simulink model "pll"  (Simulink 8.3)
settings: Solver=ode45  StartTime=0.0  StopTime=3e-08  RelTol=1e-3

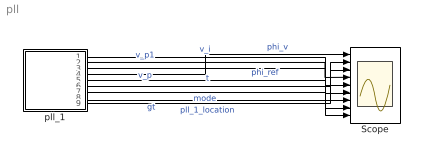
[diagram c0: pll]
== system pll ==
  Scope : Scope  NumInputPorts=9
  pll_1 : Stateflow chart  TreatAsAtomicUnit=on
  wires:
  pll_1/4(phi_v_out) -> Scope/1  "phi_v"
  pll_1/6(t_out) -> Scope/2  "t"
  pll_1/9(pll_1_location) -> Scope/3  "pll_1_location"
  pll_1/2(v_p1_out) -> Scope/4  "v_p1"
  pll_1/5(phi_ref_out) -> Scope/5  "phi_ref"
  pll_1/3(v_p_out) -> Scope/6  "v_p"
  pll_1/8(gt_out) -> Scope/7  "gt"
  pll_1/1(v_i_out) -> Scope/8  "v_i"
  pll_1/7(mode_out) -> Scope/9  "mode"

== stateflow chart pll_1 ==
  state up_1
    du:
    v_i_dot = Ii_up / C_i;
    v_p1_dot = -1 * v_p1 / C_p1 * (1 / R_p2 + 1 / R_p3) + v_p / (C_p1 * R_p3) + Ip_up / C_p1;
    v_p_dot = v_p1 / (C_p3 * R_p3) - v_p / (C_p3 * R_p3);
    phi_v_dot = v_i * K_i / N + v_p * K_p / N + 6.28 * f_0 / N;
    phi_ref_dot = 6.28 * f_ref;
    mode_dot = 0;
    gt_dot = 1;
    v_i_out=v_i;
    v_p1_out=v_p1;
    v_p_out=v_p;
    phi_v_out=phi_v;
    phi_ref_out=phi_ref;
    t_out=t;
    mode_out=mode;
    gt_out=gt;
    pll_1_location =1;
  state both_0
    du:
    v_i_dot = 0;
    v_p1_dot = -1 * v_p1 / C_p1 * (1 / R_p2 + 1 / R_p3) + v_p / (C_p1 * R_p3);
    v_p_dot = v_p1 / (C_p3 * R_p3) - v_p / (C_p3 * R_p3);
    phi_v_dot = v_i * K_i / N + v_p * K_p / N + 6.28 * f_0 / N;
    phi_ref_dot = 6.28 * f_ref;
    mode_dot = 0;
    gt_dot = 1;
    v_i_out=v_i;
    v_p1_out=v_p1;
    v_p_out=v_p;
    phi_v_out=phi_v;
    phi_ref_out=phi_ref;
    t_out=t;
    mode_out=mode;
    gt_out=gt;
    pll_1_location =2;
  state dn_1
    du:
    v_i_dot = Ii_dn / C_i;
    v_p1_dot = -1 * v_p1 / C_p1 * (1 / R_p2 + 1 / R_p3) + v_p / (C_p1 * R_p3) + Ip_dn / C_p1;
    v_p_dot = v_p1 / (C_p3 * R_p3) - v_p / (C_p3 * R_p3);
    phi_v_dot = v_i * K_i / N + v_p * K_p / N + 6.28 * f_0 / N;
    phi_ref_dot = 6.28 * f_ref;
    mode_dot = 0;
    gt_dot = 1;
    v_i_out=v_i;
    v_p1_out=v_p1;
    v_p_out=v_p;
    phi_v_out=phi_v;
    phi_ref_out=phi_ref;
    t_out=t;
    mode_out=mode;
    gt_out=gt;
    pll_1_location =3;
  state both_1
    du:
    v_i_dot = (Ii_up + Ii_dn) / C_i;
    v_p1_dot = -1 * v_p1 / C_p1 * (1 / R_p2 + 1 / R_p3) + v_p / (C_p1 * R_p3) + (Ip_up + Ip_dn) / C_p1;
    v_p_dot = v_p1 / (C_p3 * R_p3) - v_p / (C_p3 * R_p3);
    phi_v_dot = v_i * K_i / N + v_p * K_p / N + 6.28 * f_0 / N;
    phi_ref_dot = 6.28 * f_ref;
    mode_dot = 0;
    gt_dot = 1;
    v_i_out=v_i;
    v_p1_out=v_p1;
    v_p_out=v_p;
    phi_v_out=phi_v;
    phi_ref_out=phi_ref;
    t_out=t;
    mode_out=mode;
    gt_out=gt;
    pll_1_location =4;
  up_1 -> both_1 : [phi_v == 0] {t = 0; mode = 3;}
  both_1 -> both_0 : [t == t_d] {mode = 1;}
  both_0 -> dn_1 : [phi_v == 2 * 3.14] {phi_v = 0; phi_ref = phi_ref - 2 * 3.14; mode = 4;}
  (default) -> both_0 : {v_i = 0.35; v_p1 = 0; v_p = 0; phi_v = -2.5120000000000005; t = 0; gt = 0; mode = 1; phi_ref = 0;}
  both_0 -> up_1 : [phi_ref == 2 * 3.14] {phi_v = phi_v - 2 * 3.14; phi_ref = 0; mode = 2;}
  dn_1 -> both_1 : [phi_ref == 0] {t = 0;}
